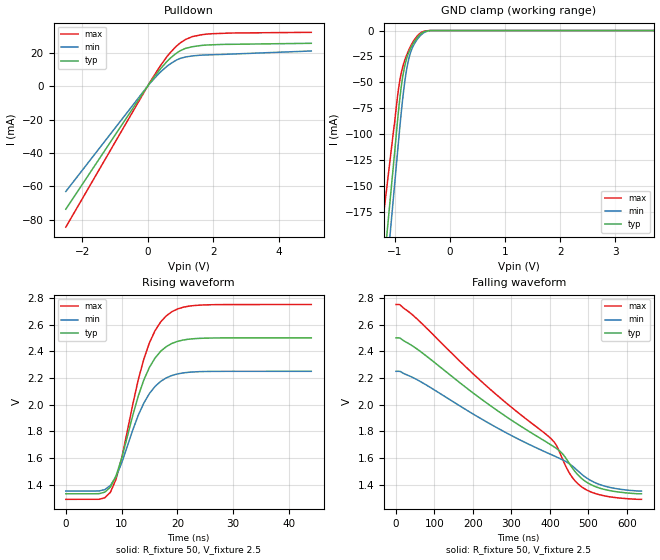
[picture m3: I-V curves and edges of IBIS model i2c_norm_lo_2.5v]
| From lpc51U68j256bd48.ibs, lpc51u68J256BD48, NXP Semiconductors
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[Model]   i2c_norm_lo_2.5v
Model_type I/O_open_drain
Vinl=4.000E-01
Vinh=1.500E+00
Vref=2.500E+00
Rref=1.000E+03
Cref=0.000E+00
Vmeas=1.250E+00
C_comp   1.270E-12   1.260E-12   1.280E-12
[Voltage Range]   2.500E+00   2.250E+00   2.750E+00
[POWER Clamp Reference]   2.500E+00   2.250E+00   2.750E+00
[GND Clamp Reference]   0.000E+00   0.000E+00   0.000E+00
[Pullup Reference]   2.500E+00   2.250E+00   2.750E+00
[Pulldown Reference]   0.000E+00   0.000E+00   0.000E+00
[Temperature Range]   25   105   -40
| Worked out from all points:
|   slope of the pulldown table from 0 to 0.375 V, typ, clamps not added: 37.8 ohm
|   GND clamp passes 1 mA (typ) near -0.46 V on its own axis
|   rising waveform, R_fixture 50, V_fixture 2.5: 20-80 % time 5.08ns typ, 5.1ns min, 5.04ns max; typ from 1.33 V to 2.5 V
|   falling waveform, R_fixture 50, V_fixture 2.5: 20-80 % time 327ns typ, 340ns min, 315ns max; typ from 2.5 V to 1.33 V
[GND Clamp]
-2.5V     -964.4mA   -1.027A    -757.5mA
-1.02V    -127.5mA   -158.8mA   -95.82mA
-940mV    -81.91mA   -111.8mA   -59.51mA
-880mV    -53.48mA   -78.11mA   -40.46mA
-840mV    -39.81mA   -58.64mA   -32.22mA
-780mV    -26.39mA   -36.23mA   -23.19mA
-740mV    -20.43mA   -26.19mA   -18.2mA
-680mV    -13.81mA   -16.61mA   -11.91mA
-600mV    -7.43mA    -9.158mA   -5.819mA
-500mV    -2.202mA   -3.199mA   -1.366mA
-340mV    0A         0A         0A
5V        0A         0A         0A
[Pulldown]
-2.5V     -73.63mA   -63.04mA   -84.39mA
80mV      2.274mA    1.887mA    2.654mA
340mV     9.059mA    7.415mA    10.69mA
600mV     14.97mA    12.03mA    17.94mA
860mV     19.41mA    15.37mA    23.55mA
980mV     20.98mA    16.46mA    25.59mA
1.16V     22.6mA     17.44mA    27.9mA
1.36V     23.56mA    18.06mA    29.59mA
1.8V      24.59mA    18.67mA    31.12mA
2.56V     25.02mA    19.18mA    31.77mA
5V        25.62mA    21.02mA    32.19mA
[Rising Waveform]
R_fixture = 50
V_fixture = 2.5
V_fixture_min = 2.25
V_fixture_max = 2.75
0s        1.333V     1.354V     1.292V
6ns       1.334V     1.355V     1.292V
8ns       1.384V     1.396V     1.345V
10ns      1.596V     1.562V     1.598V
13ns      2.067V     1.923V     2.189V
14ns      2.187V     2.014V     2.343V
16ns      2.35V      2.137V     2.554V
18ns      2.435V     2.201V     2.665V
23ns      2.494V     2.246V     2.742V
44ns      2.5V       2.25V      2.75V
[Falling Waveform]
R_fixture = 50
V_fixture = 2.5
V_fixture_min = 2.25
V_fixture_max = 2.75
0s        2.5V       2.25V      2.75V
11ns      2.498V     2.249V     2.746V
44ns      2.438V     2.203V     2.67V
233ns     2.019V     1.875V     2.146V
403ns     1.699V     1.627V     1.746V
418ns     1.671V     1.608V     1.69V
452ns     1.553V     1.555V     1.482V
479ns     1.457V     1.489V     1.393V
538ns     1.369V     1.395V     1.32V
638ns     1.333V     1.354V     1.292V
[Ramp]
dV/dt_r   6.9999E-01/5.0350E-09   5.3761E-01/5.0460E-09   8.7483E-01/5.0220E-09
dV/dt_f   6.9999E-01/3.2746E-07   5.3761E-01/3.3997E-07   8.7483E-01/3.1481E-07
R_load = 50
